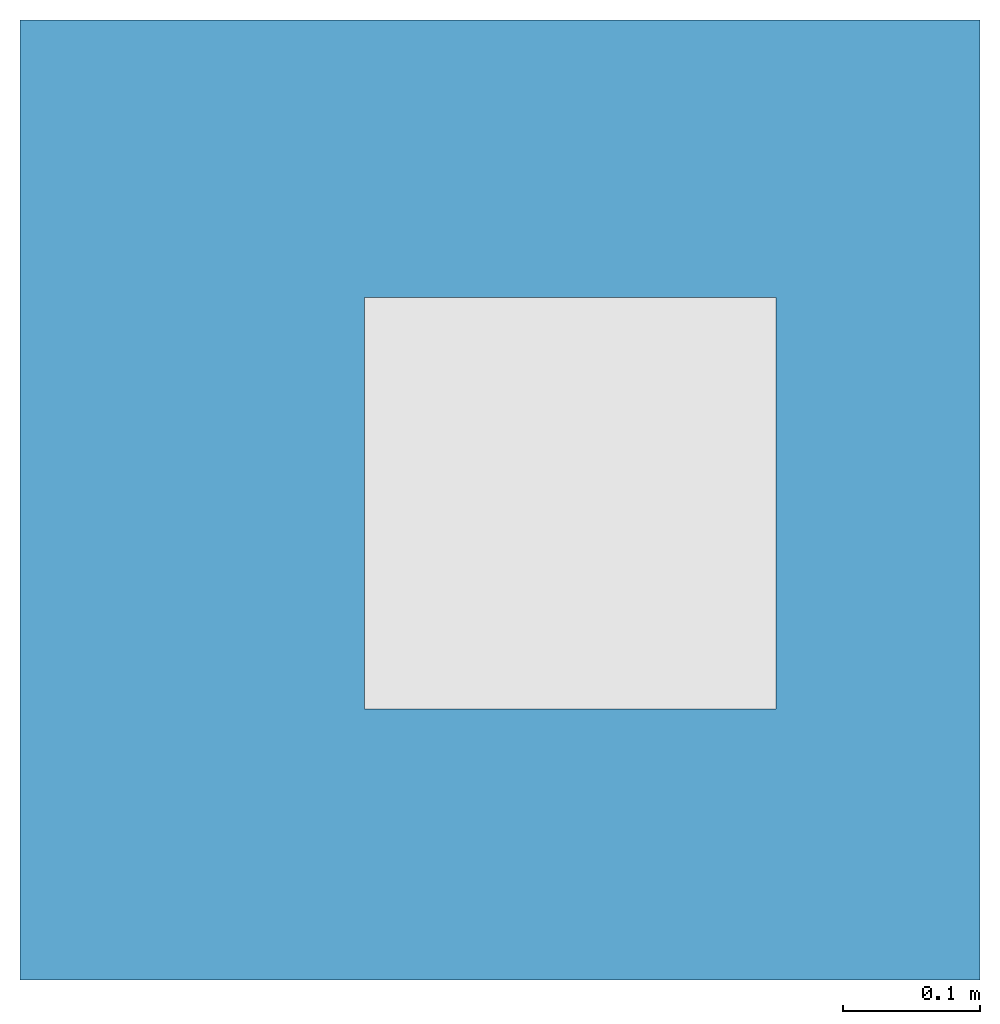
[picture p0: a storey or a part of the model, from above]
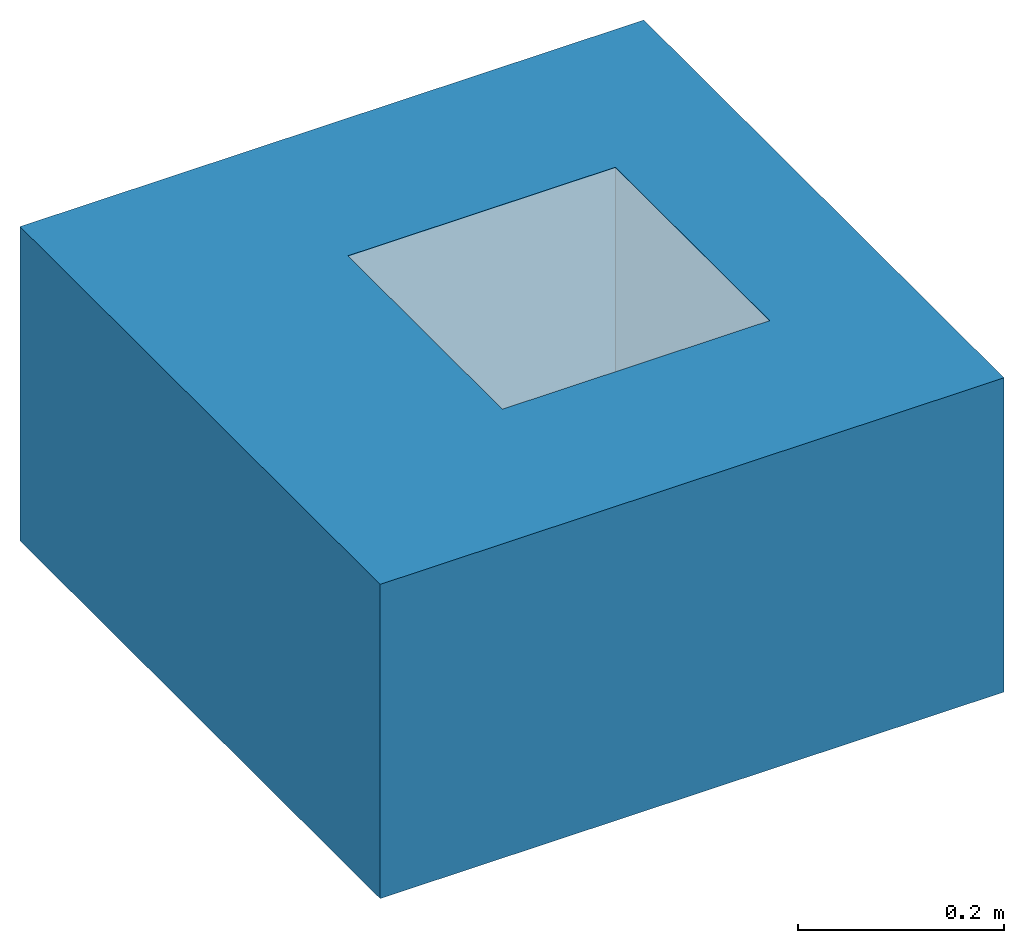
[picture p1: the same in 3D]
Properties of the parts of a building model (IFC2X3)

# File
Description: ViewDefinition [CoordinationView]
File name: Project Number
Time: 2014-10-13T17:57:48
Written by: The EXPRESS Data Manager Version 5.01.0100.02.64mod : 6 Jun 2012
Made in: 20130308_1515(x64) - Exporter 2014.0.2013.0308 - Default UI
Comment: STEP Physical File produced by: The EXPRESS Data Manager Version 5.01.0100.02.64mod : 6 Jun 2012 * Module: EDMstepFileFactory/EDMstandAlone * Creation date: Mon Oct 13 17:57:48 2014 * Host: IN-BLR-PC-0012 * Database: C:\Users\pponnur\AppData\Local\Temp\{B4E6E1E5-4179-4504-BFE5-2AE569C6722F}\ifc * Database version: 5507 * Database creation date: Mon Oct 13 17:57:47 2014 * Schema: IFC2X3 * Model: DataRepository.ifc * Model creation date: Mon Oct 13 17:57:48 2014 * Header model: DataRepository.ifc_HeaderModel * Header model creation date: Mon Oct 13 17:57:48 2014 * EDMuser: sdai-user * EDMgroup: sdai-group * License ID and type: 5605 : Permanent license. Expiry date: * EDMstepFileFactory options: 020000

# IfcProject, Project Number
LongName: Project Name; Phase: Project Status

# IfcSite, Default
RefLatitude: 42, 21, 30, 344238; RefLongitude: -71, -3, -35, -194702; RefElevation: 0 mm

# IfcBuilding
Pset_BuildingCommon - NumberOfStoreys: 1
Other - Project Name: Project Name; Project Number: Project Number; Client Name: Owner; Project Address: Enter address here; Project Issue Date: Issue Date; Project Status: Project Status

# IfcBuildingStorey, Level 1
LongName: Level 1; Elevation: 0 mm
Constraints - Elevation Base: Project Base Point; Elevation: 0 mm
Graphics - Line Weight: 1; Line Pattern: Grid Line 1/2"; Color: 0; Symbol at End 1 Default: no; Symbol: Level Head - Circle: Level Head - Circle; Symbol at End 2 Default: yes
Identity Data - Building Story: yes; Name: Level 1; Structural: no
Dimensions - Computation Height: 0 mm

# IfcFlowTerminal: 408067 Body / 408228 Top - 160mm Dia Outlet, ACO BD Gully 218 Telescopic - Square Top - Vertical Outlet with Location Flange - 300x300:408067 Body / 408228 Top - 160mm Dia Outlet:187132
In: Level 1
Material: Stainless Steel AISI 304, Rubber, Nitrile
Identity Data - Mark: 1; Water Mark 1: This file is the property of ACO Technologies PLC; Website: www.acobd.com; Manufacturer: ACO Building Drainage; Water Mark 2: This file is water marked and users are prohibited to reproduce, adapt, distribute this information; Watermarked By: www.acobd.com; Water Marked With: BIM Manager Premium Suite; Fax: +44 (0)1462 851490; E-mail Technical: abdtechnical@aco.co.uk; Telephone: +44 (0)1462 816666; E-mail Sales: abdcommercial@aco.co.uk; Address: ACO Business Centre, Caxton Road, Bedford, MK41 0LF
Construction - 408038 - 268 x 268mm - Ladder Grating - Plain - Stainless Steel 304: no; 408041 - 268 x 268mm - Arla Grating - Slip Resistant - Stainless Steel 304: no; 408042 - 268 x 268mm - Volcano Grating - Slip Resistant - Stainless Steel 304: no; 408222 - Silt Basket: yes; 408037 - 268 x 268mm - Ladder Grating - Slip Resistant - Stainless steel 304: no; 408220 - Foul Air Trap & 408221 - Foul Air Trap Support Ring: yes; 408036 - 268 x 268mm - Quadrato Grating - Brushed - Stainless steel 304: no; 408045 - 268 x 268mm - Ladder Grating - Plain - Stainless Steel 304: no; 408034 - 268 x 268mm - Mesh Grating - Slip Resistant - Stainless Steel 304: no; 408035 - 268 x 268mm - Mesh Grating - Plain - Stainless Steel 304: no; 408040 - 268 x 268mm - HeelSafe Grating - Brushed - Stainless Steel 304: no; 408039 - 268 x 268mm - Slot Cover - Plain - Stainless Steel 304: no; 160 mm Dia Outlet: yes; 110 mm Dia Outlet: no
Other - Raising Piece: no; Raising Piece Height: 500 mm; Floor Void Depth: -315 mm; Floor Top To First Layer: 68 mm; Floor To Gully Height: 68 mm; Raising Piece Detail: no; Gully Outlet Radius: 80 mm; Gully Outlet Depth: 77 mm
Constraints - Level: Level: Level 1
Model Properties - Raising Piece Product Code 408209: NA; Grating Product Code 408045: Load Class C250 (EN 1253) - Ladder Grating - Plain - Stainless steel 1.4301 (EN 10088) - 268 x 268 x 30mm; Grating Product Code 408042: Load Class M125 (EN 1253) - Volcano Grating - Slip Resistant - Stainless steel 1.4301 (EN 10088) - 268 x 268 x 30mm; Product Code 408225: Friction Ring Installation Set - Nitrile; Grating Product Code 408036: Load Class L15 (EN 1253) - Quadrato Grating - Brushed - Stainless steel 1.4301 (EN 10088) - 268 x 268 x 30mm; Grating Product Code 408041: Load Class L15 (EN 1253) - Arla Grating - Slip Resistant - Stainless steel 1.4301 (EN 10088) - 268 x 268 x 30mm; Grating Product Code 408034: Load Class L15 (EN 1253) - Mesh Grating - Slip Resistant - Stainless steel 1.4301 (EN 10088) - 268 x 268 x 30mm; Product Code 408220: Foul Air Trap - Stainless Steel 304; Product Code 408222: Silt Basket - Stainless Steel 304; Grating Product Code 408037: Load Class M125 (EN 1253) - Ladder Grating - Slip Resistant - Stainless steel 1.4301 (EN 10088) - 268 x 268 x 30mm; Product Code 408221: Foul Air Trap Support Ring - Nitrile; Grating Product Code 408038: Load Class M125 (EN 1253) - Ladder Grating -Plain - Stainless steel 1.4301 (EN 10088) - 268 x 268 x 30mm; Grating Product Code 408039: Load Class M125 (EN 1253) - Slot Cover - Plain - Stainless steel 1.4301 (EN 10088) - 268 x 268 x 30mm; Grating Product Code 408035: Load Class L15 (EN 1253) - Mesh Grating – Plain - Stainless steel 1.4301 (EN 10088) - 268 x 268 x 30mm; Grating Product Code 408040: Load Class L15 (EN 1253) - Heelsafe Grating - Brushed - Stainless steel 1.4301 (EN 10088) - 268 x 268 x 30mm
Mechanical - System Classification: Sanitary
Phasing - Phase Created: New Construction
Pset_ManufacturerTypeInformation - Manufacturer: ACO Building Drainage
General - Gully Colour: passivated stainless steel surface ( matt grey); Product Standard: EN 1253; Gully Product Description: ACO Gully 218 Telescopic Flange Type DN160 Vertical with Foul Air Trap; Foul Air Trap Seal Recycled Material Content: 0%; Foul Air Trap Seal Recyclable: Fully recyclable; Product Range: ACO Gully 218; Gully Top Size (mm): 242mm Diameter; Flow Rate (l/s): 5.0 - 6.3 l/s; Outlet Diameter (mm): 160; Load Class: A15 - C250 (EN 1253); Gully Product Code: 408067; Gully Top Product Description: ACO Gully 218 Telescopic Top for Concrete, Tiled or Resin Floor; Foul Air Trap Seal Colour: Black; Installation guidelines: http://issuu.com/acobuildingdrainage/docs/120820112708-138bdc871b784edfa2b6b8197acfd881?e=0; NBS Specification: R11 ABOVE GROUND FOUL DRAINAGE SYSTEMS : Clause 315; Gully Material: Stainless Steel Grade 304 (EN 1253); Gully Recyclable: Fully recyclable Fully recyclable; Price: POA - contact ACO; Gully top Grate size (mm): 300 x 300; Gully Recycled Material Content: 20 - 30 %; Gully Top Product Code: 408228; Gully Flange Type: Location; Product Type: Point drainage; Maintenance guidelines: http://issuu.com/acobuildingdrainage/docs/120820112708-138bdc871b784edfa2b6b8197acfd881?e=0; Foul Air Trap Seal Material: NBR
Materials and Finishes - Material: Stainless Steel AISI 304

# IfcSlab: Floor:Generic - 12", Floor:Generic - 12":184145
In: Level 1
PredefinedType: FLOOR; Material: Plywood, Sheathing 68 mm, Default Floor 304.8 mm
Dimensions - Volume: 5.44983 ft3; Perimeter: 2800 mm; Thickness: 372.8 mm; Area: 5.27432 ft2
Phasing - Phase Created: New Construction
Structural - Enable Analytical Model: no; Structural: no
Constraints - Room Bounding: yes; Related to Mass: no; Height Offset From Level: 0 mm; Level: Level: Level 1
Pset_SlabCommon - Reference: Generic - 12"; IsExternal: no; LoadBearing: yes; ThermalTransmittance: 1.55882 kg/K/s3; PitchAngle: 0 deg
Identity Data - Assembly Code: B1010; Assembly Description: Floor Construction
Analytical Properties - Thermal Resistance (R): 0.641509; Heat Transfer Coefficient (U): 1.55882; Thermal mass: 53301.1; Roughness: 3; Absorptance: 0.7
Construction - Default Thickness: 372.8 mm; Function: Interior
Graphics - Coarse Scale Fill Color: 0
